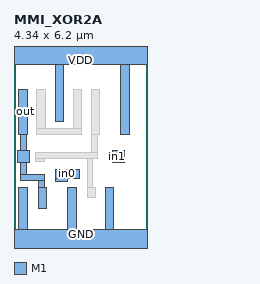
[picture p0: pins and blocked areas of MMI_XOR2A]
MACRO MMI_XOR2A
	CLASS CORE ;
	FOREIGN MMI_XOR2A 0 0 ;
	SIZE 4.34 BY 6.2 ;
	SYMMETRY X Y ;
	SITE CORE1 ;
	PIN out
		DIRECTION output ;
		USE SIGNAL ;
		PORT
			LAYER M1 ;
			RECT 0.16 3.51 0.44 4.98 ;
			LAYER M1 ;
			RECT 0.22 2.98 0.41 3.51 ;
			LAYER M1 ;
			RECT 0.12 2.6 0.5 2.98 ;
			LAYER M1 ;
			RECT 0.22 2.19 0.41 2.6 ;
			LAYER M1 ;
			RECT 0.22 2 0.985 2.19 ;
			LAYER M1 ;
			RECT 0.795 1.78 0.985 2 ;
			LAYER M1 ;
			RECT 0.795 1.08 1.075 1.78 ;
		END
		AntennaDiffArea 0.9471 ;
	END out
	PIN in1
		DIRECTION input ;
		USE SIGNAL ;
		PORT
			LAYER M1 ;
			RECT 3.22 2.93 3.6 2.98 ;
			LAYER M1 ;
			RECT 3.11 2.65 3.6 2.93 ;
			LAYER M1 ;
			RECT 3.22 2.6 3.6 2.65 ;
		END
		AntennaGateArea 0.63525 ;
	END in1
	PIN GND
		DIRECTION inout ;
		USE GROUND ;
		PORT
			LAYER M1 ;
			RECT 0.16 0.42 0.44 1.78 ;
			LAYER M1 ;
			RECT 1.755 0.42 2.035 1.78 ;
			LAYER M1 ;
			RECT 2.975 0.42 3.255 1.78 ;
			LAYER M1 ;
			RECT 0 -0.42 4.34 0.42 ;
		END
	END GND
	PIN VDD
		DIRECTION inout ;
		USE POWER ;
		PORT
			LAYER M1 ;
			RECT 0 5.78 4.34 6.62 ;
			LAYER M1 ;
			RECT 1.34 3.92 1.62 5.78 ;
			LAYER M1 ;
			RECT 3.48 3.51 3.76 5.78 ;
		END
	END VDD
	PIN in0
		DIRECTION input ;
		USE SIGNAL ;
		PORT
			LAYER M1 ;
			RECT 1.36 2.08 2.125 2.36 ;
			LAYER M1 ;
			RECT 1.36 1.98 1.74 2.08 ;
		END
		AntennaGateArea 0.63525 ;
	END in0
	OBS
		LAYER M1 ;
		RECT 0.75 3.7 1.03 4.98 ;
		LAYER M1 ;
		RECT 1.93 3.7 2.21 4.98 ;
		LAYER M1 ;
		RECT 0.75 3.505 2.21 3.7 ;
		LAYER M1 ;
		RECT 2.52 3.51 2.8 4.98 ;
		LAYER M1 ;
		RECT 0.705 2.915 0.985 2.92 ;
		LAYER M1 ;
		RECT 2.52 2.915 2.71 3.51 ;
		LAYER M1 ;
		RECT 0.705 2.725 2.71 2.915 ;
		LAYER M1 ;
		RECT 0.705 2.64 0.985 2.725 ;
		LAYER M1 ;
		RECT 2.385 1.78 2.575 2.725 ;
		LAYER M1 ;
		RECT 2.385 1.465 2.665 1.78 ;
	END
END MMI_XOR2A
